VERSION 5.7 ;
  NOWIREEXTENSIONATPIN ON ;
  DIVIDERCHAR "/" ;
  BUSBITCHARS "[]" ;
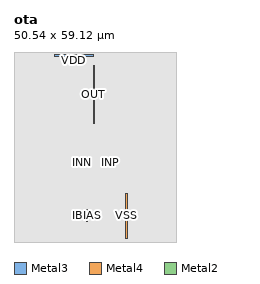
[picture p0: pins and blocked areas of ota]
MACRO ota
  CLASS BLOCK ;
  FOREIGN ota ;
  ORIGIN 25.260 3.940 ;
  SIZE 50.540 BY 59.120 ;
  PIN IBIAS
    ANTENNAGATEAREA 68.000000 ;
    ANTENNADIFFAREA 1.200000 ;
    PORT
      LAYER Metal3 ;
        RECT -2.680 2.300 -2.400 6.100 ;
    END
  END IBIAS
  PIN OUT
    ANTENNADIFFAREA 13.200000 ;
    PORT
      LAYER Metal4 ;
        RECT -0.640 32.900 -0.360 50.980 ;
    END
  END OUT
  PIN INN
    ANTENNAGATEAREA 16.000000 ;
    PORT
      LAYER Metal2 ;
        RECT -4.170 20.550 -3.890 20.830 ;
    END
  END INN
  PIN INP
    ANTENNAGATEAREA 16.000000 ;
    PORT
      LAYER Metal2 ;
        RECT 4.690 20.550 4.970 20.830 ;
    END
  END INP
  PIN VSS
    USE GROUND ;
    PORT
      LAYER Metal4 ;
        RECT 9.420 -2.800 9.980 11.200 ;
    END
  END VSS
  PIN VDD
    USE POWER ;
    PORT
      LAYER Metal3 ;
        RECT -12.600 53.900 -0.640 54.460 ;
    END
  END VDD
  OBS
      LAYER Nwell ;
        RECT -22.040 0.000 22.040 50.770 ;
      LAYER Metal1 ;
        RECT -21.810 0.210 21.810 50.560 ;
      LAYER Metal2 ;
        RECT -22.170 21.130 22.190 50.560 ;
        RECT -22.170 20.250 -4.470 21.130 ;
        RECT -3.590 20.250 4.390 21.130 ;
        RECT 5.270 20.250 22.190 21.130 ;
        RECT -22.170 0.210 22.190 20.250 ;
      LAYER Metal3 ;
        RECT -25.260 53.600 -12.900 54.460 ;
        RECT -0.340 53.600 25.280 54.460 ;
        RECT -25.260 6.400 25.280 53.600 ;
        RECT -25.260 2.000 -2.980 6.400 ;
        RECT -2.100 2.000 25.280 6.400 ;
        RECT -25.260 -3.220 25.280 2.000 ;
      LAYER Metal4 ;
        RECT -25.230 51.280 25.250 54.430 ;
        RECT -25.230 32.600 -0.940 51.280 ;
        RECT -0.060 32.600 25.250 51.280 ;
        RECT -25.230 11.500 25.250 32.600 ;
        RECT -25.230 -3.100 9.120 11.500 ;
        RECT 10.280 -3.100 25.250 11.500 ;
        RECT -25.230 -3.220 25.250 -3.100 ;
      LAYER Metal5 ;
        RECT -25.230 -3.940 25.250 55.180 ;
  END
END ota
END LIBRARY

